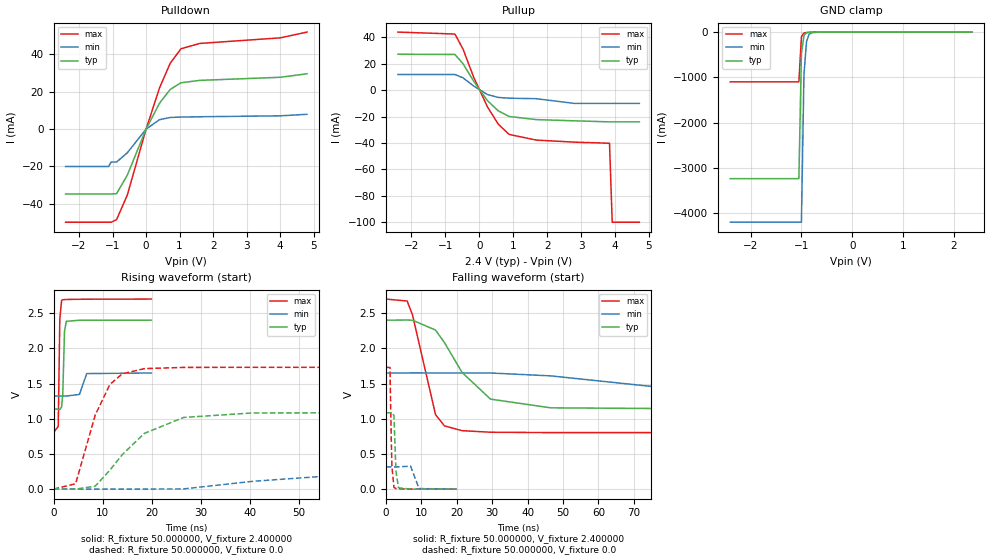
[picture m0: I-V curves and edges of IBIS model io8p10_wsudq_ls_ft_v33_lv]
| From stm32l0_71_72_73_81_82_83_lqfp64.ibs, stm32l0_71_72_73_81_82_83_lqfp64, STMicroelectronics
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|   Model io8p10_wsudq_ls_ft_v33_lv
[Model]  io8p10_wsudq_ls_ft_v33_lv
Model_type I/O
Polarity   Non-Inverting
Enable   Active-Low
Vinl =   0.720000V
Vinh =   1.680000V
Vmeas =  1.200000V
Cref =   50.000000pF
Rref =   100.000000M
Vref =   0.0V
C_comp   2.582000pF   2.574200pF   2.601000pF
[Temperature Range]   25.000000   0.105000k   -40.000000
[Pullup Reference]   2.400000V   1.650000V   2.700000V
[Pulldown Reference]   0.0V   0.0V   0.0V
[POWER Clamp Reference]   2.400000V   1.650000V   2.700000V
[GND Clamp Reference]   0.0V   0.0V   0.0V
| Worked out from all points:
|   slope of the pulldown table from 0 to 0.36 V, typ, clamps not added: 28.5 ohm
|   slope of the pullup table from 0 to 0.36 V, typ, clamps not added: 32.2 ohm
|   GND clamp passes 1 mA (typ) near -0.65 V on its own axis
|   rising waveform, R_fixture 50.000000, V_fixture 2.400000: 20-80 % time 278ps typ, 631ps min, 193ps max; typ from 1.14 V to 2.4 V
|   rising waveform, R_fixture 50.000000, V_fixture 0.0: 20-80 % time 9.33ns typ, 24.7ns min, 4.81ns max; typ from 0 V to 1.08 V
|   falling waveform, R_fixture 50.000000, V_fixture 2.400000: 20-80 % time 10.1ns typ, 27.2ns min, 4.95ns max; typ from 2.4 V to 1.14 V
|   falling waveform, R_fixture 50.000000, V_fixture 0.0: 20-80 % time 476ps typ, 849ps min, 376ps max; typ from 1.08 V to 0 V
[Pulldown]
|Voltage   I(typ)   I(min)   I(max)
-2.4V     -34.7mA    -20mA      -49.82mA
-1.12V    -34.7mA    -20mA      -49.82mA
-1.04V    -34.7mA    -17.6mA    -49.82mA
-880mV    -34.55mA   -17.6mA    -48.46mA
-560mV    -24.65mA   -12.68mA   -35.33mA
0V        0A         0A         16fA
400mV     13.84mA    5.066mA    22.03mA
720mV     21.25mA    6.254mA    35.26mA
1.04V     24.82mA    6.464mA    43.03mA
1.6V      26.11mA    6.627mA    45.88mA
4V        27.76mA    7.125mA    48.87mA
4.8V      29.63mA    7.94mA     51.96mA
[Pullup]
|Voltage   I(typ)   I(min)   I(max)
-2.4V     27.21mA    11.89mA    44.01mA
-720mV    27.06mA    11.89mA    42.53mA
-480mV    20.06mA    9.352mA    31.11mA
-160mV    6.586mA    3.048mA    9.467mA
240mV     -7.917mA   -3.299mA   -12.65mA
560mV     -15.67mA   -5.497mA   -25.76mA
880mV     -19.92mA   -6.062mA   -33.51mA
1.68V     -22.29mA   -6.449mA   -37.81mA
2.8V      -23.2mA    -10mA      -39.35mA
3.84V     -24mA      -10mA      -40.2mA
3.92V     -24mA      -10mA      -100mA
4.72V     -24mA      -10mA      -100mA
[GND_clamp]
|Voltage   I(typ)   I(min)   I(max)
-2.4V     -3.237A    -4.198A    -1.1A
-1.05V    -3.237A    -4.198A    -1.1A
-1V       -475.9mA   -4.198A    -104.3mA
-950mV    -76.36mA   -935.5mA   -18.56mA
-900mV    -16.77mA   -213mA     -9.293mA
-850mV    -6.713mA   -51.08mA   -6.724mA
-800mV    -4.108mA   -13.94mA   -4.924mA
-650mV    -1.048mA   -1.2mA     -1.149mA
2.35V     0A         0A         0A
[POWER_clamp]
|Voltage   I(typ)   I(min)   I(max)
-2.4V     0A         0A         0A
0V        0A         0A         0A
[Ramp]
| variable   typ   min   max
dV/dt_r  0.65070/9.31539n   0.18997/24.65135n   1.03800/4.80236n
dV/dt_f  0.75690/10.06462n   0.19674/27.13717n   1.13815/4.93316n
R_load = 50.000000
[Rising Waveform]
R_fixture= 50.000000
V_fixture= 2.400000
V_fixture_min= 1.650000
V_fixture_max= 2.700000
|time   V(typ)   V(min)   V(max)
0s        1.139V     1.322V     803.1mV
961ps     1.135V     1.322V     890.6mV
1.281ns   1.131V     1.322V     2.413V
1.642ns   1.167V     1.322V     2.68V
1.882ns   1.346V     1.322V     2.69V
2.242ns   2.245V     1.322V     2.693V
2.603ns   2.384V     1.322V     2.694V
5.285ns   2.399V     1.345V     2.697V
6.767ns   2.399V     1.641V     2.698V
19.94ns   2.4V       1.65V      2.7V
[Rising Waveform]
R_fixture= 50.000000
V_fixture= 0.0
V_fixture_min= 0.0
V_fixture_max= 0.0
|time   V(typ)   V(min)   V(max)
0s        1.461nV    7.27nV     1.206nV
4.505ns   -918.5uV   120uV      76.23mV
8.509ns   41.82mV    -240.6uV   1.054V
11.51ns   270.8mV    -199.4uV   1.489V
14.01ns   489.2mV    -201.1uV   1.637V
18.52ns   792.1mV    -169.6uV   1.712V
26.53ns   1.018V     3.012mV    1.729V
40.54ns   1.082V     110.2mV    1.73V
79.58ns   1.085V     302.7mV    1.73V
249.2ns   1.085V     316.6mV    1.73V
[Falling Waveform]
R_fixture= 50.000000
V_fixture= 2.400000
V_fixture_min= 1.650000
V_fixture_max= 2.700000
|time   V(typ)   V(min)   V(max)
0s        2.4V       1.65V      2.7V
6.006ns   2.402V     1.65V      2.672V
7.508ns   2.4V       1.652V     2.477V
14.01ns   2.26V      1.65V      1.061V
16.52ns   2.083V     1.65V      899mV
21.52ns   1.657V     1.65V      830.8mV
29.53ns   1.279V     1.65V      808.7mV
46.55ns   1.155V     1.609V     803.3mV
96.6ns    1.139V     1.345V     803.1mV
249.2ns   1.139V     1.322V     803.1mV
[Falling Waveform]
R_fixture= 50.000000
V_fixture= 0.0
V_fixture_min= 0.0
V_fixture_max= 0.0
|time   V(typ)   V(min)   V(max)
0s        1.085V     316.6mV    1.73V
1.161ns   1.085V     316.6mV    1.728V
1.522ns   1.084V     316.6mV    706.4mV
1.722ns   1.089V     316.6mV    313.4mV
2.282ns   1.045V     316.6mV    25.75mV
2.843ns   257.7mV    316.6mV    7.815mV
3.564ns   19.26mV    316.6mV    4.809mV
6.967ns   1.021mV    326.9mV    1.307mV
9.369ns   553.1uV    8.943mV    419.6uV
19.94ns   1.461nV    7.27nV     1.206nV
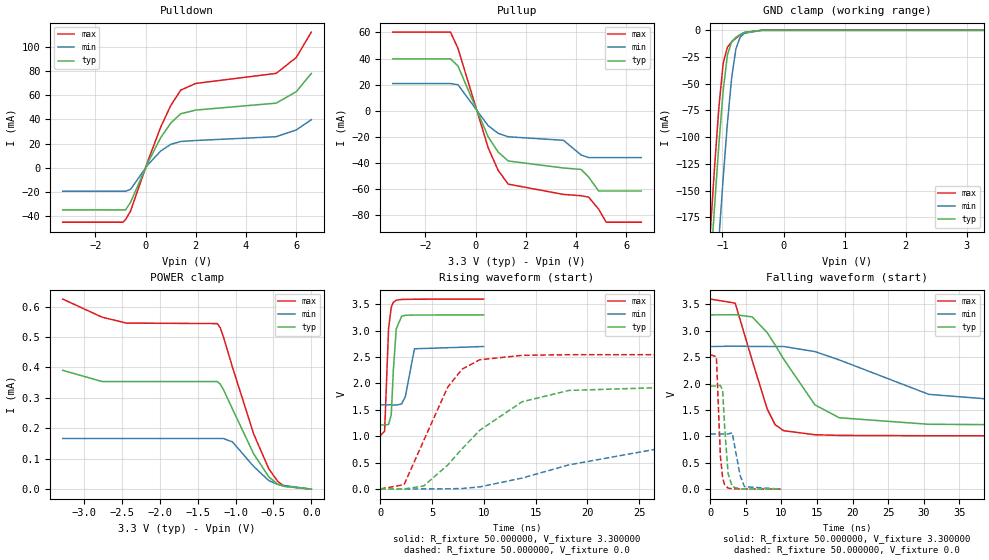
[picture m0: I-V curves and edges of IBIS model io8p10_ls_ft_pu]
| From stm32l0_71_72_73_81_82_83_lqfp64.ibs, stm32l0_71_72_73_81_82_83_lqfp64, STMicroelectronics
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|   Model io8p10_ls_ft_pu
[Model]  io8p10_ls_ft_pu
Model_type I/O
Polarity   Non-Inverting
Enable   Active-Low
Vinl =   0.990000V
Vinh =   2.310000V
Vmeas =  1.650000V
Cref =   50.000000pF
Rref =   100.000000M
Vref =   0.0V
C_comp   4.606100pF   4.563500pF   4.706200pF
[Temperature Range]   25.000000   0.125000k   -40.000000
[Pullup Reference]   3.300000V   2.700000V   3.600000V
[Pulldown Reference]   0.0V   0.0V   0.0V
[POWER Clamp Reference]   3.300000V   2.700000V   3.600000V
[GND Clamp Reference]   0.0V   0.0V   0.0V
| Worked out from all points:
|   slope of the pulldown table from 0 to 0.495 V, typ, clamps not added: 23.6 ohm
|   slope of the pullup table from 0 to 0.495 V, typ, clamps not added: 24.9 ohm
|   GND clamp passes 1 mA (typ) near -0.59 V on its own axis
|   rising waveform, R_fixture 50.000000, V_fixture 3.300000: 20-80 % time 316ps typ, 425ps min, 299ps max; typ from 1.22 V to 3.3 V
|   rising waveform, R_fixture 50.000000, V_fixture 0.0: 20-80 % time 6.51ns typ, 13.6ns min, 3.48ns max; typ from 0.001 V to 1.95 V
|   falling waveform, R_fixture 50.000000, V_fixture 3.300000: 20-80 % time 6.08ns typ, 12.5ns min, 3.34ns max; typ from 3.3 V to 1.22 V
|   falling waveform, R_fixture 50.000000, V_fixture 0.0: 20-80 % time 528ps typ, 690ps min, 463ps max; typ from 1.95 V to 0.001 V
[Pulldown]
|Voltage   I(typ)   I(min)   I(max)
-3.3V     -34.78mA   -19.34mA   -44.89mA
-900mV    -34.78mA   -19.34mA   -44.89mA
-800mV    -34.78mA   -19.34mA   -42.84mA
-600mV    -28.56mA   -17.8mA    -35.75mA
100mV     4.638mA    2.744mA    6.076mA
600mV     24.8mA     13.84mA    33.52mA
1V        36.93mA    19.4mA     51.35mA
1.4V      44.67mA    21.76mA    64.17mA
2V        47.71mA    22.58mA    69.7mA
5.2V      53.42mA    25.71mA    78.01mA
6V        62.87mA    31.27mA    91.1mA
6.6V      77.92mA    39.75mA    112.1mA
[Pullup]
|Voltage   I(typ)   I(min)   I(max)
-3.3V     39.76mA    20.84mA    60.3mA
-1V       39.76mA    20.84mA    60.3mA
-700mV    34.25mA    19.9mA     47.76mA
500mV     -20.02mA   -11.5mA    -28.37mA
900mV     -31.73mA   -17.35mA   -45.82mA
1.3V      -38.59mA   -20.02mA   -56.34mA
3.5V      -43.94mA   -22.7mA    -64.24mA
4.2V      -45.07mA   -33.96mA   -65.24mA
4.5V      -50.83mA   -35.99mA   -66.3mA
4.9V      -61.63mA   -35.99mA   -75.49mA
5.2V      -61.63mA   -35.99mA   -85.54mA
6.6V      -61.63mA   -35.99mA   -85.54mA
[GND_clamp]
|Voltage   I(typ)   I(min)   I(max)
-3.3V     -2.276A    -2.356A    -2.25A
-1.2V     -226mA     -318.7mA   -189.2mA
-1.13V    -164.9mA   -256.6mA   -128.3mA
-1.06V    -107.5mA   -196.5mA   -72.78mA
-990mV    -57.32mA   -139.4mA   -31.39mA
-920mV    -23.22mA   -87.32mA   -15.73mA
-850mV    -10.58mA   -44.45mA   -10.94mA
-780mV    -6.539mA   -17.25mA   -7.356mA
-710mV    -3.933mA   -6.349mA   -4.308mA
-640mV    -1.955mA   -2.79mA    -1.975mA
-360mV    -2.06uA    -16.21uA   -459.5nA
3.28V     0A         0A         0A
[POWER_clamp]
|Voltage   I(typ)   I(min)   I(max)
-3.28V    390.5uA    166.4uA    624.7uA
-2.76V    353.6uA    166.4uA    565.1uA
-2.44V    353.6uA    166.4uA    545.7uA
-1.24V    353.6uA    166.4uA    544.1uA
-1.2V     344.6uA    166.4uA    529.4uA
-1.16V    327.5uA    166.4uA    501.1uA
-1.04V    263.2uA    155.2uA    400.5uA
-760mV    115.6uA    74.53uA    180.9uA
-560mV    40.33uA    28.04uA    66.46uA
-440mV    15.38uA    15.6uA     24.56uA
-360mV    9.136uA    12.12uA    10.1uA
0V        0A         0A         0A
[Ramp]
| variable   typ   min   max
dV/dt_r  1.17099/6.50627n   0.61910/13.54742n   1.52743/3.48068n
dV/dt_f  1.25052/6.06896n   0.63966/12.41549n   1.55250/3.33267n
R_load = 50.000000
[Rising Waveform]
R_fixture= 50.000000
V_fixture= 3.300000
V_fixture_min= 2.700000
V_fixture_max= 3.600000
|time   V(typ)   V(min)   V(max)
0s        1.215V     1.595V     1.012V
420.4ps   1.214V     1.595V     1.096V
800.8ps   1.224V     1.595V     3.037V
1.061ns   1.408V     1.595V     3.446V
1.261ns   2.24V      1.593V     3.538V
1.542ns   3.033V     1.591V     3.578V
2.062ns   3.273V     1.611V     3.592V
2.422ns   3.292V     1.75V      3.593V
3.303ns   3.297V     2.657V     3.596V
9.97ns    3.3V       2.7V       3.599V
[Rising Waveform]
R_fixture= 50.000000
V_fixture= 0.0
V_fixture_min= 0.0
V_fixture_max= 0.0
|time   V(typ)   V(min)   V(max)
0s        1.271mV    1.914mV    1.653mV
2.302ns   483.7uV    -2.067mV   83.72mV
4.204ns   59.27mV    3.286mV    921.1mV
6.507ns   453.6mV    4.177mV    1.927V
7.908ns   763.9mV    10.42mV    2.272V
9.61ns    1.114V     40.99mV    2.449V
13.71ns   1.654V     208.4mV    2.533V
18.22ns   1.868V     457.9mV    2.545V
31.53ns   1.95V      928mV      2.546V
49.85ns   1.953V     1.046V     2.546V
[Falling Waveform]
R_fixture= 50.000000
V_fixture= 3.300000
V_fixture_min= 2.700000
V_fixture_max= 3.600000
|time   V(typ)   V(min)   V(max)
0s        3.3V       2.7V       3.599V
3.504ns   3.303V     2.709V     3.522V
5.906ns   3.261V     2.702V     2.431V
8.008ns   2.962V     2.702V     1.518V
9.109ns   2.732V     2.701V     1.223V
10.31ns   2.464V     2.701V     1.108V
14.71ns   1.597V     2.605V     1.031V
18.12ns   1.353V     2.448V     1.019V
30.73ns   1.229V     1.795V     1.012V
49.85ns   1.215V     1.595V     1.012V
[Falling Waveform]
R_fixture= 50.000000
V_fixture= 0.0
V_fixture_min= 0.0
V_fixture_max= 0.0
|time   V(typ)   V(min)   V(max)
0s        1.953V     1.046V     2.546V
860.9ps   1.953V     1.046V     2.507V
1.421ns   1.964V     1.046V     626mV
1.742ns   1.869V     1.046V     210.7mV
2.022ns   1.173V     1.046V     83.81mV
2.503ns   297.8mV    1.046V     21.97mV
3.083ns   49.24mV    1.067V     8.838mV
4.184ns   5.698mV    266.3mV    6.434mV
4.805ns   4.79mV     48.07mV    4.383mV
9.97ns    1.271mV    1.914mV    1.653mV
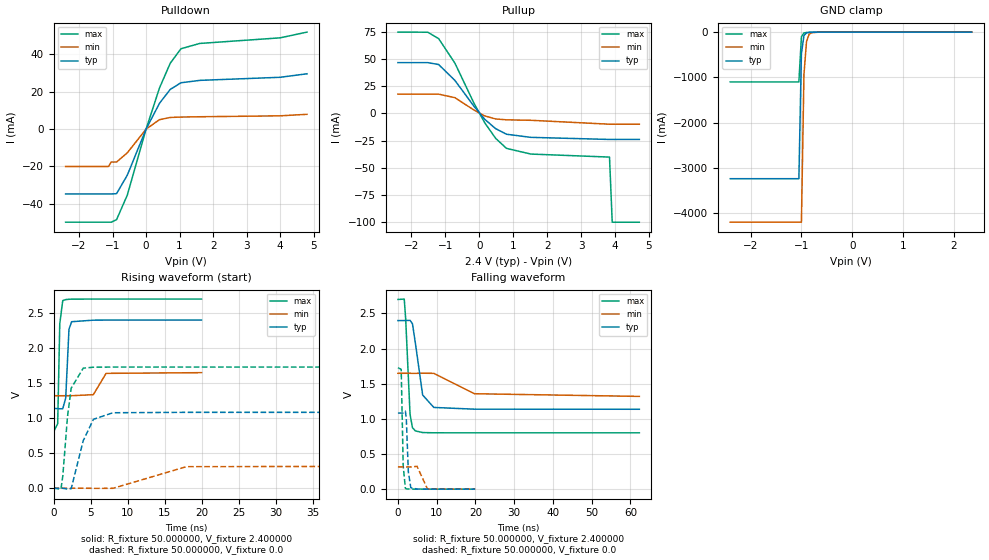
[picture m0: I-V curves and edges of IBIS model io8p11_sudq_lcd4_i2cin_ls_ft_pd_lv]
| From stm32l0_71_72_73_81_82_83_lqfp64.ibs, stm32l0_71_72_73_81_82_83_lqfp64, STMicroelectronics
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|   Model io8p11_sudq_lcd4_i2cin_ls_ft_pd_lv
[Model]  io8p11_sudq_lcd4_i2cin_ls_ft_pd_lv
Model_type I/O
Polarity   Non-Inverting
Enable   Active-Low
Vinl =   0.720000V
Vinh =   1.680000V
Vmeas =  1.200000V
Cref =   50.000000pF
Rref =   100.000000M
Vref =   0.0V
C_comp   2.470900pF   2.435200pF   2.490500pF
[Temperature Range]   25.000000   0.105000k   -40.000000
[Pullup Reference]   2.400000V   1.650000V   2.700000V
[Pulldown Reference]   0.0V   0.0V   0.0V
[POWER Clamp Reference]   2.400000V   1.650000V   2.700000V
[GND Clamp Reference]   0.0V   0.0V   0.0V
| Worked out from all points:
|   slope of the pulldown table from 0 to 0.36 V, typ, clamps not added: 28.5 ohm
|   slope of the pullup table from 0 to 0.36 V, typ, clamps not added: 32.2 ohm
|   GND clamp passes 1 mA (typ) near -0.64 V on its own axis
|   rising waveform, R_fixture 50.000000, V_fixture 2.400000: 20-80 % time 284ps typ, 638ps min, 195ps max; typ from 1.14 V to 2.4 V
|   rising waveform, R_fixture 50.000000, V_fixture 0.0: 20-80 % time 1.58ns typ, 3.83ns min, 925ps max; typ from 0 V to 1.08 V
|   falling waveform, R_fixture 50.000000, V_fixture 2.400000: 20-80 % time 1.8ns typ, 5.35ns min, 905ps max; typ from 2.4 V to 1.14 V
|   falling waveform, R_fixture 50.000000, V_fixture 0.0: 20-80 % time 463ps typ, 840ps min, 362ps max; typ from 1.08 V to 0 V
[Pulldown]
|Voltage   I(typ)   I(min)   I(max)
-2.4V     -34.7mA    -20mA      -49.82mA
-1.12V    -34.7mA    -20mA      -49.82mA
-1.04V    -34.7mA    -17.6mA    -49.82mA
-880mV    -34.55mA   -17.6mA    -48.46mA
-560mV    -24.65mA   -12.68mA   -35.33mA
0V        224fA      0A         16fA
400mV     13.84mA    5.066mA    22.03mA
720mV     21.25mA    6.254mA    35.26mA
1.04V     24.83mA    6.464mA    43.03mA
1.6V      26.11mA    6.627mA    45.88mA
4V        27.76mA    7.125mA    48.88mA
4.8V      29.64mA    7.94mA     51.96mA
[Pullup]
|Voltage   I(typ)   I(min)   I(max)
-2.4V     46.57mA    17.61mA    74.62mA
-1.52V    46.57mA    17.61mA    74.5mA
-1.2V     44.84mA    17.61mA    68.61mA
-720mV    30.25mA    14.38mA    46.12mA
-160mV    6.59mA     3.051mA    9.467mA
160mV     -5.477mA   -2.361mA   -8.695mA
480mV     -14.04mA   -5.167mA   -22.91mA
800mV     -19.2mA    -5.978mA   -32.18mA
1.52V     -22.07mA   -6.4mA     -37.42mA
3.84V     -24mA      -10mA      -40.2mA
3.92V     -24mA      -10mA      -100mA
4.72V     -24mA      -10mA      -100mA
[GND_clamp]
|Voltage   I(typ)   I(min)   I(max)
-2.4V     -3.237A    -4.197A    -1.1A
-1.05V    -3.237A    -4.197A    -1.1A
-1V       -475.5mA   -4.197A    -104.1mA
-950mV    -76.09mA   -935.1mA   -18.45mA
-900mV    -16.59mA   -212.6mA   -9.272mA
-850mV    -6.633mA   -50.89mA   -6.773mA
-800mV    -4.105mA   -13.86mA   -5.003mA
-650mV    -1.082mA   -1.227mA   -1.183mA
2.35V     52.69uA    50.02uA    36.84uA
[POWER_clamp]
|Voltage   I(typ)   I(min)   I(max)
-2.4V     0A         0A         0A
0V        0A         0A         0A
[Ramp]
| variable   typ   min   max
dV/dt_r  0.65004/1.57938n   0.18967/3.82548n   1.03746/0.92208n
dV/dt_f  0.75702/1.79356n   0.19614/5.33447n   1.13800/0.90320n
R_load = 50.000000
[Rising Waveform]
R_fixture= 50.000000
V_fixture= 2.400000
V_fixture_min= 1.650000
V_fixture_max= 2.700000
|time   V(typ)   V(min)   V(max)
0s        1.137V     1.32V      801.7mV
560.6ps   1.137V     1.32V      921.3mV
840.8ps   1.134V     1.32V      2.347V
1.241ns   1.134V     1.32V      2.677V
1.642ns   1.287V     1.32V      2.692V
2.082ns   2.269V     1.32V      2.696V
2.442ns   2.376V     1.32V      2.698V
5.365ns   2.398V     1.335V     2.699V
7.087ns   2.399V     1.639V     2.699V
19.94ns   2.399V     1.649V     2.699V
[Rising Waveform]
R_fixture= 50.000000
V_fixture= 0.0
V_fixture_min= 0.0
V_fixture_max= 0.0
|time   V(typ)   V(min)   V(max)
0s        -2.929uV   4.053uV    227uV
1.001ns   109.5uV    1.262uV    -13.29mV
1.251ns   -712.4uV   -1.605uV   176mV
1.877ns   -10.76mV   -5.065uV   1.016V
2.377ns   -7.638mV   10.78uV    1.427V
4.004ns   679.4mV    87.89uV    1.713V
5.38ns    983.6mV    -1.515mV   1.727V
8.008ns   1.077V     -1.141mV   1.729V
17.89ns   1.083V     307.5mV    1.729V
62.31ns   1.083V     316.1mV    1.729V
[Falling Waveform]
R_fixture= 50.000000
V_fixture= 2.400000
V_fixture_min= 1.650000
V_fixture_max= 2.700000
|time   V(typ)   V(min)   V(max)
0s        2.399V     1.649V     2.699V
1.627ns   2.399V     1.649V     2.705V
2.002ns   2.4V       1.649V     2.421V
3.128ns   2.402V     1.649V     1.065V
3.754ns   2.353V     1.648V     874.3mV
4.505ns   2.078V     1.648V     829mV
6.381ns   1.34V      1.65V      805.5mV
9.259ns   1.163V     1.648V     802.1mV
19.77ns   1.138V     1.358V     801.7mV
62.31ns   1.137V     1.32V      801.7mV
[Falling Waveform]
R_fixture= 50.000000
V_fixture= 0.0
V_fixture_min= 0.0
V_fixture_max= 0.0
|time   V(typ)   V(min)   V(max)
0s        1.083V     316.1mV    1.729V
840.8ps   1.083V     316.1mV    1.705V
1.361ns   1.083V     316.1mV    327.3mV
1.922ns   1.11V      316.1mV    14.41mV
2.162ns   1.004V     316.1mV    4.309mV
2.683ns   247.4mV    315.9mV    2.024mV
3.323ns   21.03mV    315.8mV    1.309mV
4.925ns   1.512mV    325.7mV    490.4uV
7.608ns   356.3uV    5.653mV    251.2uV
19.94ns   -2.929uV   4.053uV    227uV
